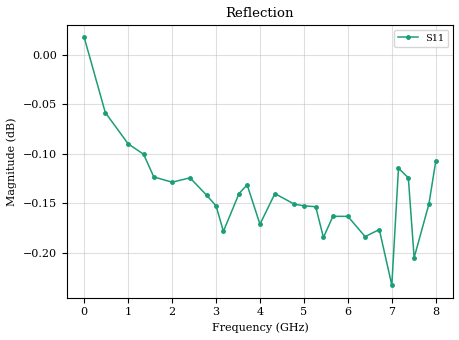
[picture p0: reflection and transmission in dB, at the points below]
!  22/10/2019  12:30:56
! Ref Plane: 0.000 mm
# MHZ S MA R  50
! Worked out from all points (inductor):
!   2001 points, 300 kHz to 8 GHz, reference 50 ohm
!   read as one part to ground: L = 2.31 nH near 40.3 MHz
!   highest Q = 69.3 at 2.408 GHz (marker M1), where L = 2.89 nH
!   self-resonance near 5.25 GHz
!   S11 on the Smith chart (normalised r, x): 300 kHz: -0.00, +0.00; 1.584 GHz: 0.01, +0.51; 3.168 GHz: 0.03, +1.41; 4.776 GHz: 0.50, +7.50; 6.392 GHz: 0.09, -2.71; 8 GHz: 0.01, -0.90
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0.3  1.002 179.8
480.288  0.9933 163.7
1000.275  0.9897 146.2
1352.266  0.9885 134.2
1584.26  0.9859 126.4
2000.25  0.9853 111.9
2408.24  0.9858 97.7
2788.23  0.9838 83.8
3000.225  0.9826 76.6
3168.221  0.9797 70.7
3524.212  0.984 58.0
3708.207  0.985 51.6
4000.2  0.9805 41.8
4340.191  0.984 30.0
4776.181  0.9828 15.1
5000.175  0.9826 7.5
5268.168  0.9825 -0.6
5444.164  0.979 -7.3
5660.158  0.9814 -15.2
6000.15  0.9814 -25.4
6392.14  0.9791 -40.5
6716.132  0.9799 -50.0
7000.125  0.9736 -61.3
7152.121  0.9869 -68.0
7376.116  0.9858 -74.0
7508.112  0.9767 -77.3
7844.104  0.9828 -92.1
8000.1  0.9877 -96.1
